VERSION 5.7 ;
  NOWIREEXTENSIONATPIN ON ;
  DIVIDERCHAR "/" ;
  BUSBITCHARS "[]" ;
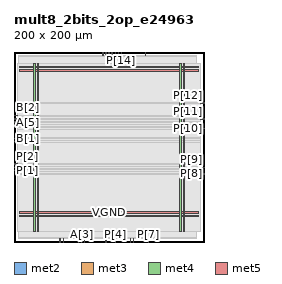
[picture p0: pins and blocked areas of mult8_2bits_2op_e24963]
MACRO mult8_2bits_2op_e24963
  CLASS BLOCK ;
  FOREIGN mult8_2bits_2op_e24963 ;
  ORIGIN 0.000 0.000 ;
  SIZE 200.000 BY 200.000 ;
  PIN A[0]
    DIRECTION INPUT ;
    USE SIGNAL ;
    ANTENNAGATEAREA 0.196500 ;
    PORT
      LAYER met2 ;
        RECT 48.390 0.000 48.670 4.000 ;
    END
  END A[0]
  PIN A[1]
    DIRECTION INPUT ;
    USE SIGNAL ;
    ANTENNAGATEAREA 0.126000 ;
    PORT
      LAYER met2 ;
        RECT 51.610 0.000 51.890 4.000 ;
    END
  END A[1]
  PIN A[2]
    DIRECTION INPUT ;
    USE SIGNAL ;
    ANTENNAGATEAREA 0.495000 ;
    PORT
      LAYER met2 ;
        RECT 74.150 0.000 74.430 4.000 ;
    END
  END A[2]
  PIN A[3]
    DIRECTION INPUT ;
    USE SIGNAL ;
    ANTENNAGATEAREA 0.213000 ;
    PORT
      LAYER met2 ;
        RECT 70.930 0.000 71.210 4.000 ;
    END
  END A[3]
  PIN A[4]
    DIRECTION INPUT ;
    USE SIGNAL ;
    ANTENNAGATEAREA 0.196500 ;
    PORT
      LAYER met3 ;
        RECT 0.000 122.440 4.000 123.040 ;
    END
  END A[4]
  PIN A[5]
    DIRECTION INPUT ;
    USE SIGNAL ;
    ANTENNAGATEAREA 0.213000 ;
    PORT
      LAYER met3 ;
        RECT 0.000 125.840 4.000 126.440 ;
    END
  END A[5]
  PIN A[6]
    DIRECTION INPUT ;
    USE SIGNAL ;
    ANTENNAGATEAREA 0.196500 ;
    PORT
      LAYER met2 ;
        RECT 96.690 196.000 96.970 200.000 ;
    END
  END A[6]
  PIN A[7]
    DIRECTION INPUT ;
    USE SIGNAL ;
    ANTENNAGATEAREA 0.196500 ;
    PORT
      LAYER met2 ;
        RECT 103.130 196.000 103.410 200.000 ;
    END
  END A[7]
  PIN B[0]
    DIRECTION INPUT ;
    USE SIGNAL ;
    ANTENNAGATEAREA 0.196500 ;
    PORT
      LAYER met3 ;
        RECT 0.000 105.440 4.000 106.040 ;
    END
  END B[0]
  PIN B[1]
    DIRECTION INPUT ;
    USE SIGNAL ;
    ANTENNAGATEAREA 0.213000 ;
    PORT
      LAYER met3 ;
        RECT 0.000 108.840 4.000 109.440 ;
    END
  END B[1]
  PIN B[2]
    DIRECTION INPUT ;
    USE SIGNAL ;
    ANTENNAGATEAREA 0.213000 ;
    PORT
      LAYER met3 ;
        RECT 0.000 132.640 4.000 133.240 ;
    END
  END B[2]
  PIN B[3]
    DIRECTION INPUT ;
    USE SIGNAL ;
    ANTENNAGATEAREA 0.742500 ;
    PORT
      LAYER met3 ;
        RECT 0.000 129.240 4.000 129.840 ;
    END
  END B[3]
  PIN B[4]
    DIRECTION INPUT ;
    USE SIGNAL ;
    ANTENNAGATEAREA 0.126000 ;
    PORT
      LAYER met2 ;
        RECT 96.690 0.000 96.970 4.000 ;
    END
  END B[4]
  PIN B[5]
    DIRECTION INPUT ;
    USE SIGNAL ;
    ANTENNAGATEAREA 0.126000 ;
    PORT
      LAYER met2 ;
        RECT 106.350 196.000 106.630 200.000 ;
    END
  END B[5]
  PIN B[6]
    DIRECTION INPUT ;
    USE SIGNAL ;
    ANTENNAGATEAREA 0.213000 ;
    PORT
      LAYER met2 ;
        RECT 93.470 196.000 93.750 200.000 ;
    END
  END B[6]
  PIN B[7]
    DIRECTION INPUT ;
    USE SIGNAL ;
    ANTENNAGATEAREA 0.196500 ;
    PORT
      LAYER met2 ;
        RECT 99.910 196.000 100.190 200.000 ;
    END
  END B[7]
  PIN P[0]
    DIRECTION OUTPUT ;
    USE SIGNAL ;
    ANTENNADIFFAREA 0.445500 ;
    PORT
      LAYER met3 ;
        RECT 0.000 78.240 4.000 78.840 ;
    END
  END P[0]
  PIN P[10]
    DIRECTION OUTPUT ;
    USE SIGNAL ;
    ANTENNADIFFAREA 1.336500 ;
    PORT
      LAYER met3 ;
        RECT 196.000 119.040 200.000 119.640 ;
    END
  END P[10]
  PIN P[11]
    DIRECTION OUTPUT ;
    USE SIGNAL ;
    ANTENNADIFFAREA 1.336500 ;
    PORT
      LAYER met3 ;
        RECT 196.000 129.240 200.000 129.840 ;
    END
  END P[11]
  PIN P[12]
    DIRECTION OUTPUT ;
    USE SIGNAL ;
    ANTENNADIFFAREA 0.891000 ;
    PORT
      LAYER met3 ;
        RECT 196.000 146.240 200.000 146.840 ;
    END
  END P[12]
  PIN P[13]
    DIRECTION OUTPUT ;
    USE SIGNAL ;
    ANTENNADIFFAREA 1.336500 ;
    PORT
      LAYER met2 ;
        RECT 138.550 196.000 138.830 200.000 ;
    END
  END P[13]
  PIN P[14]
    DIRECTION OUTPUT ;
    USE SIGNAL ;
    ANTENNADIFFAREA 1.336500 ;
    PORT
      LAYER met2 ;
        RECT 112.790 196.000 113.070 200.000 ;
    END
  END P[14]
  PIN P[15]
    DIRECTION OUTPUT ;
    USE SIGNAL ;
    ANTENNADIFFAREA 0.891000 ;
    PORT
      LAYER met2 ;
        RECT 109.570 196.000 109.850 200.000 ;
    END
  END P[15]
  PIN P[1]
    DIRECTION OUTPUT ;
    USE SIGNAL ;
    ANTENNADIFFAREA 0.445500 ;
    PORT
      LAYER met3 ;
        RECT 0.000 74.840 4.000 75.440 ;
    END
  END P[1]
  PIN P[2]
    DIRECTION OUTPUT ;
    USE SIGNAL ;
    ANTENNADIFFAREA 0.445500 ;
    PORT
      LAYER met3 ;
        RECT 0.000 81.640 4.000 82.240 ;
    END
  END P[2]
  PIN P[3]
    DIRECTION OUTPUT ;
    USE SIGNAL ;
    ANTENNADIFFAREA 0.445500 ;
    PORT
      LAYER met2 ;
        RECT 67.710 0.000 67.990 4.000 ;
    END
  END P[3]
  PIN P[4]
    DIRECTION OUTPUT ;
    USE SIGNAL ;
    ANTENNADIFFAREA 0.445500 ;
    PORT
      LAYER met2 ;
        RECT 106.350 0.000 106.630 4.000 ;
    END
  END P[4]
  PIN P[5]
    DIRECTION OUTPUT ;
    USE SIGNAL ;
    ANTENNADIFFAREA 0.445500 ;
    PORT
      LAYER met2 ;
        RECT 122.450 0.000 122.730 4.000 ;
    END
  END P[5]
  PIN P[6]
    DIRECTION OUTPUT ;
    USE SIGNAL ;
    ANTENNADIFFAREA 1.336500 ;
    PORT
      LAYER met2 ;
        RECT 125.670 0.000 125.950 4.000 ;
    END
  END P[6]
  PIN P[7]
    DIRECTION OUTPUT ;
    USE SIGNAL ;
    ANTENNADIFFAREA 1.336500 ;
    PORT
      LAYER met2 ;
        RECT 141.770 0.000 142.050 4.000 ;
    END
  END P[7]
  PIN P[8]
    DIRECTION OUTPUT ;
    USE SIGNAL ;
    ANTENNADIFFAREA 0.891000 ;
    PORT
      LAYER met3 ;
        RECT 196.000 71.440 200.000 72.040 ;
    END
  END P[8]
  PIN P[9]
    DIRECTION OUTPUT ;
    USE SIGNAL ;
    ANTENNADIFFAREA 0.891000 ;
    PORT
      LAYER met3 ;
        RECT 196.000 78.240 200.000 78.840 ;
    END
  END P[9]
  PIN VGND
    DIRECTION INOUT ;
    USE GROUND ;
    PORT
      LAYER met4 ;
        RECT 24.340 10.640 25.940 187.920 ;
    END
    PORT
      LAYER met4 ;
        RECT 177.940 10.640 179.540 187.920 ;
    END
    PORT
      LAYER met5 ;
        RECT 5.280 30.030 194.360 31.630 ;
    END
    PORT
      LAYER met5 ;
        RECT 5.280 183.210 194.360 184.810 ;
    END
  END VGND
  PIN VPWR
    DIRECTION INOUT ;
    USE POWER ;
    PORT
      LAYER met4 ;
        RECT 21.040 10.640 22.640 187.920 ;
    END
    PORT
      LAYER met4 ;
        RECT 174.640 10.640 176.240 187.920 ;
    END
    PORT
      LAYER met5 ;
        RECT 5.280 26.730 194.360 28.330 ;
    END
    PORT
      LAYER met5 ;
        RECT 5.280 179.910 194.360 181.510 ;
    END
  END VPWR
  OBS
      LAYER nwell ;
        RECT 5.330 10.795 194.310 187.870 ;
      LAYER li1 ;
        RECT 5.520 10.795 194.120 187.765 ;
      LAYER met1 ;
        RECT 4.210 10.640 194.120 187.920 ;
      LAYER met2 ;
        RECT 4.230 195.720 93.190 196.000 ;
        RECT 94.030 195.720 96.410 196.000 ;
        RECT 97.250 195.720 99.630 196.000 ;
        RECT 100.470 195.720 102.850 196.000 ;
        RECT 103.690 195.720 106.070 196.000 ;
        RECT 106.910 195.720 109.290 196.000 ;
        RECT 110.130 195.720 112.510 196.000 ;
        RECT 113.350 195.720 138.270 196.000 ;
        RECT 139.110 195.720 192.190 196.000 ;
        RECT 4.230 4.280 192.190 195.720 ;
        RECT 4.230 4.000 48.110 4.280 ;
        RECT 48.950 4.000 51.330 4.280 ;
        RECT 52.170 4.000 67.430 4.280 ;
        RECT 68.270 4.000 70.650 4.280 ;
        RECT 71.490 4.000 73.870 4.280 ;
        RECT 74.710 4.000 96.410 4.280 ;
        RECT 97.250 4.000 106.070 4.280 ;
        RECT 106.910 4.000 122.170 4.280 ;
        RECT 123.010 4.000 125.390 4.280 ;
        RECT 126.230 4.000 141.490 4.280 ;
        RECT 142.330 4.000 192.190 4.280 ;
      LAYER met3 ;
        RECT 3.990 147.240 196.000 187.845 ;
        RECT 3.990 145.840 195.600 147.240 ;
        RECT 3.990 133.640 196.000 145.840 ;
        RECT 4.400 132.240 196.000 133.640 ;
        RECT 3.990 130.240 196.000 132.240 ;
        RECT 4.400 128.840 195.600 130.240 ;
        RECT 3.990 126.840 196.000 128.840 ;
        RECT 4.400 125.440 196.000 126.840 ;
        RECT 3.990 123.440 196.000 125.440 ;
        RECT 4.400 122.040 196.000 123.440 ;
        RECT 3.990 120.040 196.000 122.040 ;
        RECT 3.990 118.640 195.600 120.040 ;
        RECT 3.990 109.840 196.000 118.640 ;
        RECT 4.400 108.440 196.000 109.840 ;
        RECT 3.990 106.440 196.000 108.440 ;
        RECT 4.400 105.040 196.000 106.440 ;
        RECT 3.990 82.640 196.000 105.040 ;
        RECT 4.400 81.240 196.000 82.640 ;
        RECT 3.990 79.240 196.000 81.240 ;
        RECT 4.400 77.840 195.600 79.240 ;
        RECT 3.990 75.840 196.000 77.840 ;
        RECT 4.400 74.440 196.000 75.840 ;
        RECT 3.990 72.440 196.000 74.440 ;
        RECT 3.990 71.040 195.600 72.440 ;
        RECT 3.990 10.715 196.000 71.040 ;
  END
END mult8_2bits_2op_e24963
END LIBRARY

